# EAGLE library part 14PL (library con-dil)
DIL CABLE CONNECTOR

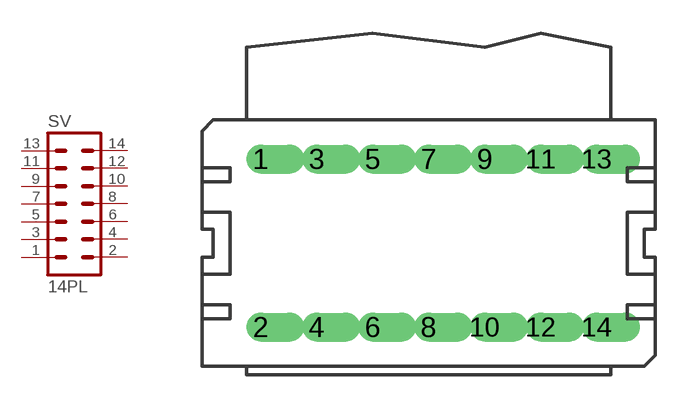
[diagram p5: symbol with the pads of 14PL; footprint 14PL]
Designator prefix SV

## 14PL  [14PL]
1  1  pas
2  2  pas
3  3  pas
4  4  pas
5  5  pas
6  6  pas
7  7  pas
8  8  pas
9  9  pas
10  10  pas
11  11  pas
12  12  pas
13  13  pas
14  14  pas

## Footprint 14PL (pad centres in mm)
DIL CABLE CONNECTOR
drill 0.813 offset: 1 -7.62,3.81; 2 -7.62,-3.81; 3 -5.08,3.81; 4 -5.08,-3.81; 5 -2.54,3.81; 6 -2.54,-3.81; 7 0,3.81; 8 0,-3.81; 9 2.54,3.81; 10 2.54,-3.81; 11 5.08,3.81; 12 5.08,-3.81; 13 7.62,3.81; 14 7.62,-3.81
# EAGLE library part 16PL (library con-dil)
DIL CABLE CONNECTOR

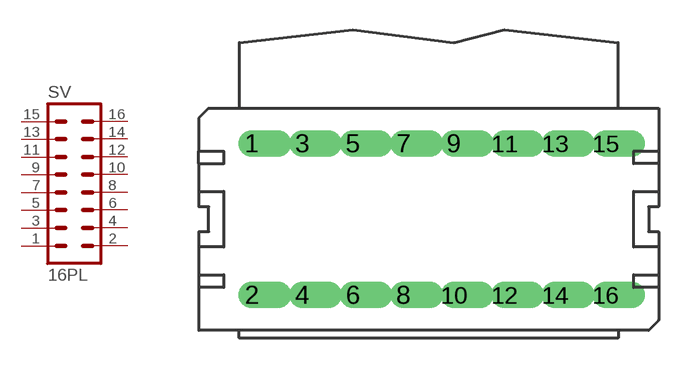
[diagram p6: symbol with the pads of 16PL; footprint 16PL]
Designator prefix SV

## 16PL  [16PL]
1  1  pas
2  2  pas
3  3  pas
4  4  pas
5  5  pas
6  6  pas
7  7  pas
8  8  pas
9  9  pas
10  10  pas
11  11  pas
12  12  pas
13  13  pas
14  14  pas
15  15  pas
16  16  pas

## Footprint 16PL (pad centres in mm)
DIL CABLE CONNECTOR
drill 0.813 offset: 1 -8.89,3.81; 2 -8.89,-3.81; 3 -6.35,3.81; 4 -6.35,-3.81; 5 -3.81,3.81; 6 -3.81,-3.81; 7 -1.27,3.81; 8 -1.27,-3.81; 9 1.27,3.81; 10 1.27,-3.81; 11 3.81,3.81; 12 3.81,-3.81; 13 6.35,3.81; 14 6.35,-3.81; 15 8.89,3.81; 16 8.89,-3.81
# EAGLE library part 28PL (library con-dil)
DIL CABLE CONNECTOR

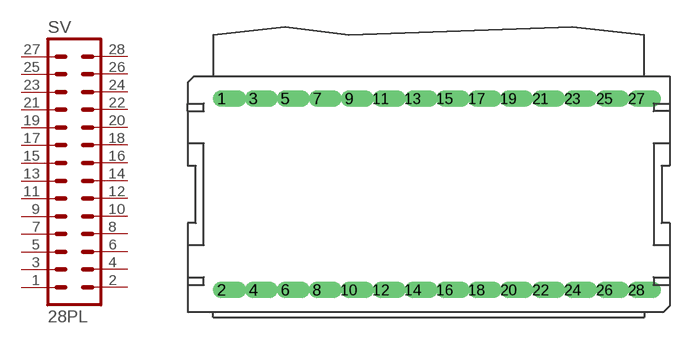
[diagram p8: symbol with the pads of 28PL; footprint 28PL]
Designator prefix SV

## 28PL  [28PL]
1  1  pas
2  2  pas
3  3  pas
4  4  pas
5  5  pas
6  6  pas
7  7  pas
8  8  pas
9  9  pas
10  10  pas
11  11  pas
12  12  pas
13  13  pas
14  14  pas
15  15  pas
16  16  pas
17  17  pas
18  18  pas
19  19  pas
20  20  pas
21  21  pas
22  22  pas
23  23  pas
24  24  pas
25  25  pas
26  26  pas
27  27  pas
28  28  pas

## Footprint 28PL (pad centres in mm)
DIL CABLE CONNECTOR
drill 0.813 offset: 1 -16.51,7.62; 2 -16.51,-7.62; 3 -13.97,7.62; 4 -13.97,-7.62; 5 -11.43,7.62; 6 -11.43,-7.62; 7 -8.89,7.62; 8 -8.89,-7.62; 9 -6.35,7.62; 10 -6.35,-7.62; 11 -3.81,7.62; 12 -3.81,-7.62; 13 -1.27,7.62; 14 -1.27,-7.62; 15 1.27,7.62; 16 1.27,-7.62; 17 3.81,7.62; 18 3.81,-7.62; 19 6.35,7.62; 20 6.35,-7.62; 21 8.89,7.62; 22 8.89,-7.62; 23 11.43,7.62; 24 11.43,-7.62; 25 13.97,7.62; 26 13.97,-7.62; 27 16.51,7.62; 28 16.51,-7.62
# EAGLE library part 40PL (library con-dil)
DIL CABLE CONNECTOR

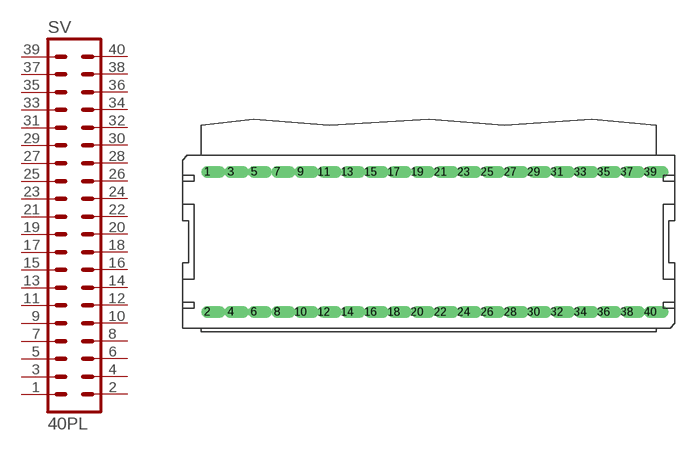
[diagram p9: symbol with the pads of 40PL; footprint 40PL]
Designator prefix SV

## 40PL  [40PL]
1  1  pas
2  2  pas
3  3  pas
4  4  pas
5  5  pas
6  6  pas
7  7  pas
8  8  pas
9  9  pas
10  10  pas
11  11  pas
12  12  pas
13  13  pas
14  14  pas
15  15  pas
16  16  pas
17  17  pas
18  18  pas
19  19  pas
20  20  pas
21  21  pas
22  22  pas
23  23  pas
24  24  pas
25  25  pas
26  26  pas
27  27  pas
28  28  pas
29  29  pas
30  30  pas
31  31  pas
32  32  pas
33  33  pas
34  34  pas
35  35  pas
36  36  pas
37  37  pas
38  38  pas
39  39  pas
40  40  pas

## Footprint 40PL (pad centres in mm)
DIL CABLE CONNECTOR
drill 0.813 offset: 1 -24.13,7.62; 2 -24.13,-7.62; 3 -21.59,7.62; 4 -21.59,-7.62; 5 -19.05,7.62; 6 -19.05,-7.62; 7 -16.51,7.62; 8 -16.51,-7.62; 9 -13.97,7.62; 10 -13.97,-7.62; 11 -11.43,7.62; 12 -11.43,-7.62; 13 -8.89,7.62; 14 -8.89,-7.62; 15 -6.35,7.62; 16 -6.35,-7.62; 17 -3.81,7.62; 18 -3.81,-7.62; 19 -1.27,7.62; 20 -1.27,-7.62; 21 1.27,7.62; 22 1.27,-7.62; 23 3.81,7.62; 24 3.81,-7.62; 25 6.35,7.62; 26 6.35,-7.62; 27 8.89,7.62; 28 8.89,-7.62; 29 11.43,7.62; 30 11.43,-7.62; 31 13.97,7.62; 32 13.97,-7.62; 33 16.51,7.62; 34 16.51,-7.62; 35 19.05,7.62; 36 19.05,-7.62; 37 21.59,7.62; 38 21.59,-7.62; 39 24.13,7.62; 40 24.13,-7.62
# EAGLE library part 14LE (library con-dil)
DIL CABLE CONNECTOR

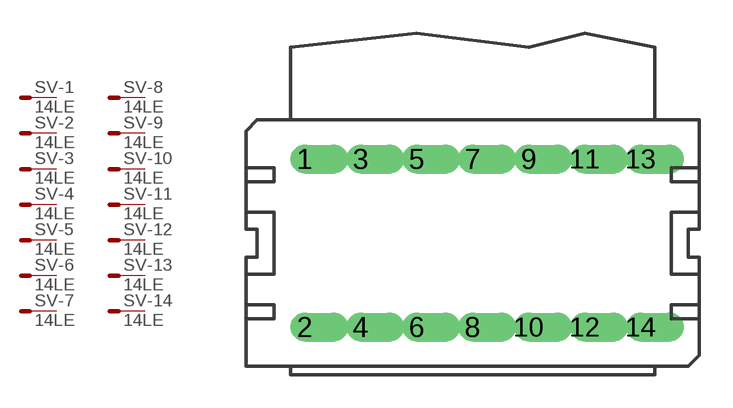
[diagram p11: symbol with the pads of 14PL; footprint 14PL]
Designator prefix SV; gates -1=ST -2=ST -3=ST -4=ST -5=ST -6=ST -7=ST -8=ST -9=ST -10=ST -11=ST -12=ST -13=ST -14=ST

## 14LE  [14PL]
1  -1:S  pas
2  -2:S  pas
3  -3:S  pas
4  -4:S  pas
5  -5:S  pas
6  -6:S  pas
7  -7:S  pas
8  -8:S  pas
9  -9:S  pas
10  -10:S  pas
11  -11:S  pas
12  -12:S  pas
13  -13:S  pas
14  -14:S  pas

## Footprint 14PL (pad centres in mm)
DIL CABLE CONNECTOR
drill 0.813 offset: 1 -7.62,3.81; 2 -7.62,-3.81; 3 -5.08,3.81; 4 -5.08,-3.81; 5 -2.54,3.81; 6 -2.54,-3.81; 7 0,3.81; 8 0,-3.81; 9 2.54,3.81; 10 2.54,-3.81; 11 5.08,3.81; 12 5.08,-3.81; 13 7.62,3.81; 14 7.62,-3.81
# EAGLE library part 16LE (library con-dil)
DIL CABLE CONNECTOR

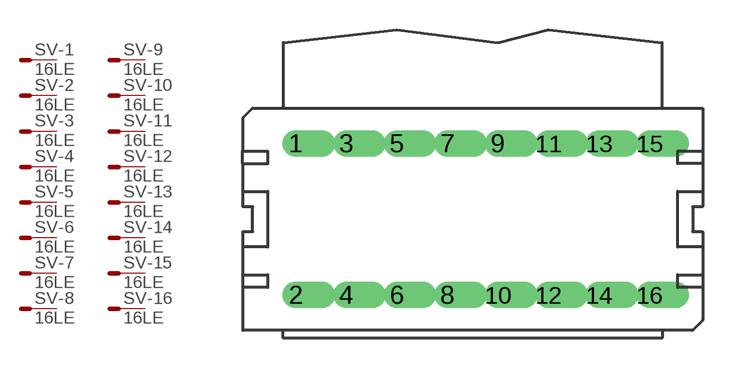
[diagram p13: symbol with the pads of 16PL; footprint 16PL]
Designator prefix SV; gates -1=ST -2=ST -3=ST -4=ST -5=ST -6=ST -7=ST -8=ST -9=ST -10=ST -11=ST -12=ST -13=ST -14=ST -15=ST -16=ST

## 16LE  [16PL]
1  -1:S  pas
2  -2:S  pas
3  -3:S  pas
4  -4:S  pas
5  -5:S  pas
6  -6:S  pas
7  -7:S  pas
8  -8:S  pas
9  -9:S  pas
10  -10:S  pas
11  -11:S  pas
12  -12:S  pas
13  -13:S  pas
14  -14:S  pas
15  -15:S  pas
16  -16:S  pas

## Footprint 16PL (pad centres in mm)
DIL CABLE CONNECTOR
drill 0.813 offset: 1 -8.89,3.81; 2 -8.89,-3.81; 3 -6.35,3.81; 4 -6.35,-3.81; 5 -3.81,3.81; 6 -3.81,-3.81; 7 -1.27,3.81; 8 -1.27,-3.81; 9 1.27,3.81; 10 1.27,-3.81; 11 3.81,3.81; 12 3.81,-3.81; 13 6.35,3.81; 14 6.35,-3.81; 15 8.89,3.81; 16 8.89,-3.81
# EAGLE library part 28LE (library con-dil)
DIL CABLE CONNECTOR

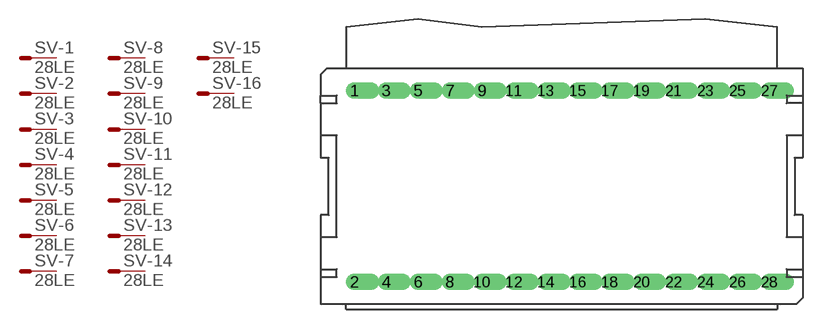
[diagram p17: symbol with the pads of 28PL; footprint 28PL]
Designator prefix SV; gates -1=ST -2=ST -3=ST -4=ST -5=ST -6=ST -7=ST -8=ST -9=ST -10=ST -11=ST -12=ST -13=ST -14=ST -15=ST -16=ST -17=ST -18=ST -19=ST -20=ST -21=ST -22=ST -23=ST -24=ST -25=ST -26=ST -27=ST -28=ST

## 28LE  [28PL]
1  -1:S  pas
2  -2:S  pas
3  -3:S  pas
4  -4:S  pas
5  -5:S  pas
6  -6:S  pas
7  -7:S  pas
8  -8:S  pas
9  -9:S  pas
10  -10:S  pas
11  -11:S  pas
12  -12:S  pas
13  -13:S  pas
14  -14:S  pas
15  -15:S  pas
16  -16:S  pas
17  -17:S  pas
18  -18:S  pas
19  -19:S  pas
20  -20:S  pas
21  -21:S  pas
22  -22:S  pas
23  -23:S  pas
24  -24:S  pas
25  -25:S  pas
26  -26:S  pas
27  -27:S  pas
28  -28:S  pas

## Footprint 28PL (pad centres in mm)
DIL CABLE CONNECTOR
drill 0.813 offset: 1 -16.51,7.62; 2 -16.51,-7.62; 3 -13.97,7.62; 4 -13.97,-7.62; 5 -11.43,7.62; 6 -11.43,-7.62; 7 -8.89,7.62; 8 -8.89,-7.62; 9 -6.35,7.62; 10 -6.35,-7.62; 11 -3.81,7.62; 12 -3.81,-7.62; 13 -1.27,7.62; 14 -1.27,-7.62; 15 1.27,7.62; 16 1.27,-7.62; 17 3.81,7.62; 18 3.81,-7.62; 19 6.35,7.62; 20 6.35,-7.62; 21 8.89,7.62; 22 8.89,-7.62; 23 11.43,7.62; 24 11.43,-7.62; 25 13.97,7.62; 26 13.97,-7.62; 27 16.51,7.62; 28 16.51,-7.62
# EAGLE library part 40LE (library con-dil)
DIL CABLE CONNECTOR

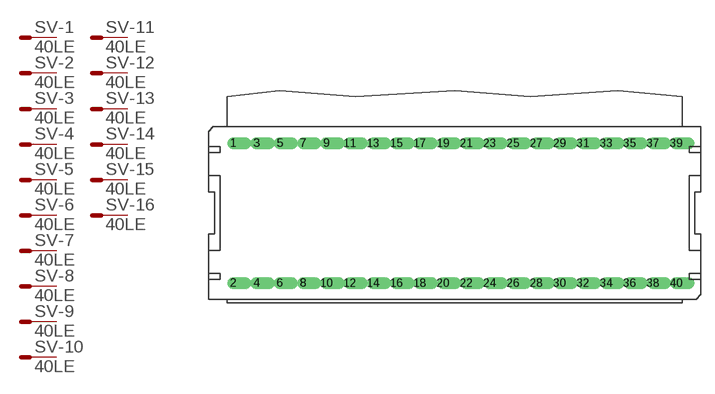
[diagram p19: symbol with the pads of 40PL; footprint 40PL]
Designator prefix SV; gates -1=ST -2=ST -3=ST -4=ST -5=ST -6=ST -7=ST -8=ST -9=ST -10=ST -11=ST -12=ST -13=ST -14=ST -15=ST -16=ST -17=ST -18=ST -19=ST -20=ST -21=ST -22=ST -23=ST -24=ST -25=ST -26=ST -27=ST -28=ST -29=ST -30=ST -31=ST -32=ST -33=ST -34=ST -35=ST -36=ST -37=ST -38=ST -39=ST -40=ST

## 40LE  [40PL]
1  -1:S  pas
2  -2:S  pas
3  -3:S  pas
4  -4:S  pas
5  -5:S  pas
6  -6:S  pas
7  -7:S  pas
8  -8:S  pas
9  -9:S  pas
10  -10:S  pas
11  -11:S  pas
12  -12:S  pas
13  -13:S  pas
14  -14:S  pas
15  -15:S  pas
16  -16:S  pas
17  -17:S  pas
18  -18:S  pas
19  -19:S  pas
20  -20:S  pas
21  -21:S  pas
22  -22:S  pas
23  -23:S  pas
24  -24:S  pas
25  -25:S  pas
26  -26:S  pas
27  -27:S  pas
28  -28:S  pas
29  -29:S  pas
30  -30:S  pas
31  -31:S  pas
32  -32:S  pas
33  -33:S  pas
34  -34:S  pas
35  -35:S  pas
36  -36:S  pas
37  -37:S  pas
38  -38:S  pas
39  -39:S  pas
40  -40:S  pas

## Footprint 40PL (pad centres in mm)
DIL CABLE CONNECTOR
drill 0.813 offset: 1 -24.13,7.62; 2 -24.13,-7.62; 3 -21.59,7.62; 4 -21.59,-7.62; 5 -19.05,7.62; 6 -19.05,-7.62; 7 -16.51,7.62; 8 -16.51,-7.62; 9 -13.97,7.62; 10 -13.97,-7.62; 11 -11.43,7.62; 12 -11.43,-7.62; 13 -8.89,7.62; 14 -8.89,-7.62; 15 -6.35,7.62; 16 -6.35,-7.62; 17 -3.81,7.62; 18 -3.81,-7.62; 19 -1.27,7.62; 20 -1.27,-7.62; 21 1.27,7.62; 22 1.27,-7.62; 23 3.81,7.62; 24 3.81,-7.62; 25 6.35,7.62; 26 6.35,-7.62; 27 8.89,7.62; 28 8.89,-7.62; 29 11.43,7.62; 30 11.43,-7.62; 31 13.97,7.62; 32 13.97,-7.62; 33 16.51,7.62; 34 16.51,-7.62; 35 19.05,7.62; 36 19.05,-7.62; 37 21.59,7.62; 38 21.59,-7.62; 39 24.13,7.62; 40 24.13,-7.62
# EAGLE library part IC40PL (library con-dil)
DIL CABLE CONNECTOR

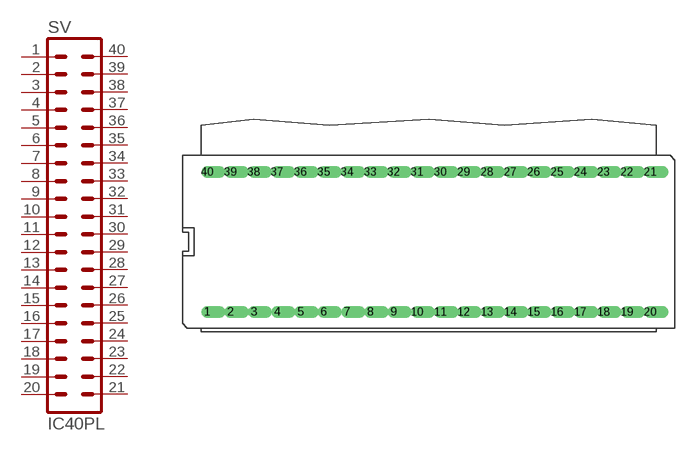
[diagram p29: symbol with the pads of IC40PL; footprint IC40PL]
Designator prefix SV

## IC40PL  [IC40PL]
1  1  pas
2  2  pas
3  3  pas
4  4  pas
5  5  pas
6  6  pas
7  7  pas
8  8  pas
9  9  pas
10  10  pas
11  11  pas
12  12  pas
13  13  pas
14  14  pas
15  15  pas
16  16  pas
17  17  pas
18  18  pas
19  19  pas
20  20  pas
21  21  pas
22  22  pas
23  23  pas
24  24  pas
25  25  pas
26  26  pas
27  27  pas
28  28  pas
29  29  pas
30  30  pas
31  31  pas
32  32  pas
33  33  pas
34  34  pas
35  35  pas
36  36  pas
37  37  pas
38  38  pas
39  39  pas
40  40  pas

## Footprint IC40PL (pad centres in mm)
DIL CABLE CONNECTOR
drill 0.813 offset: 1 -24.13,-7.62; 2 -21.59,-7.62; 3 -19.05,-7.62; 4 -16.51,-7.62; 5 -13.97,-7.62; 6 -11.43,-7.62; 7 -8.89,-7.62; 8 -6.35,-7.62; 9 -3.81,-7.62; 10 -1.27,-7.62; 11 1.27,-7.62; 12 3.81,-7.62; 13 6.35,-7.62; 14 8.89,-7.62; 15 11.43,-7.62; 16 13.97,-7.62; 17 16.51,-7.62; 18 19.05,-7.62; 19 21.59,-7.62; 20 24.13,-7.62; 21 24.13,7.62; 22 21.59,7.62; 23 19.05,7.62; 24 16.51,7.62; 25 13.97,7.62; 26 11.43,7.62; 27 8.89,7.62; 28 6.35,7.62; 29 3.81,7.62; 30 1.27,7.62; 31 -1.27,7.62; 32 -3.81,7.62; 33 -6.35,7.62; 34 -8.89,7.62; 35 -11.43,7.62; 36 -13.97,7.62; 37 -16.51,7.62; 38 -19.05,7.62; 39 -21.59,7.62; 40 -24.13,7.62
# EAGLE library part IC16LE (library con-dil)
DIL CABLE CONNECTOR

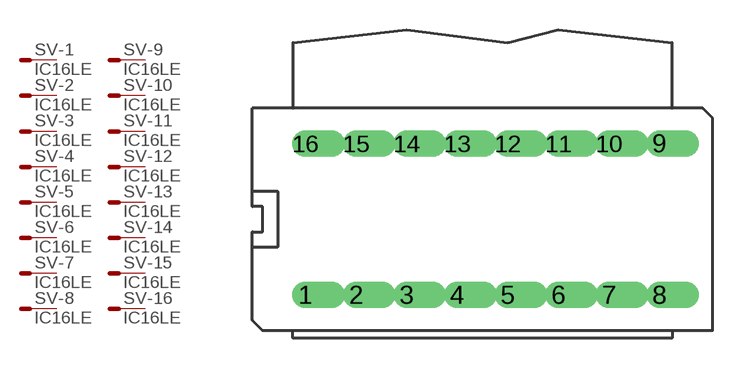
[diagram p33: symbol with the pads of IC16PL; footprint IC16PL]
Designator prefix SV; gates -1=ICST -2=ICST -3=ICST -4=ICST -5=ICST -6=ICST -7=ICST -8=ICST -9=ICST -10=ICST -11=ICST -12=ICST -13=ICST -14=ICST -15=ICST -16=ICST

## IC16LE  [IC16PL]
1  -1:S  pas
2  -2:S  pas
3  -3:S  pas
4  -4:S  pas
5  -5:S  pas
6  -6:S  pas
7  -7:S  pas
8  -8:S  pas
9  -9:S  pas
10  -10:S  pas
11  -11:S  pas
12  -12:S  pas
13  -13:S  pas
14  -14:S  pas
15  -15:S  pas
16  -16:S  pas

## Footprint IC16PL (pad centres in mm)
DIL CABLE CONNECTOR
drill 0.813 offset: 1 -8.89,-3.81; 2 -6.35,-3.81; 3 -3.81,-3.81; 4 -1.27,-3.81; 5 1.27,-3.81; 6 3.81,-3.81; 7 6.35,-3.81; 8 8.89,-3.81; 9 8.89,3.81; 10 6.35,3.81; 11 3.81,3.81; 12 1.27,3.81; 13 -1.27,3.81; 14 -3.81,3.81; 15 -6.35,3.81; 16 -8.89,3.81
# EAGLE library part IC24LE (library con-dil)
DIL CABLE CONNECTOR

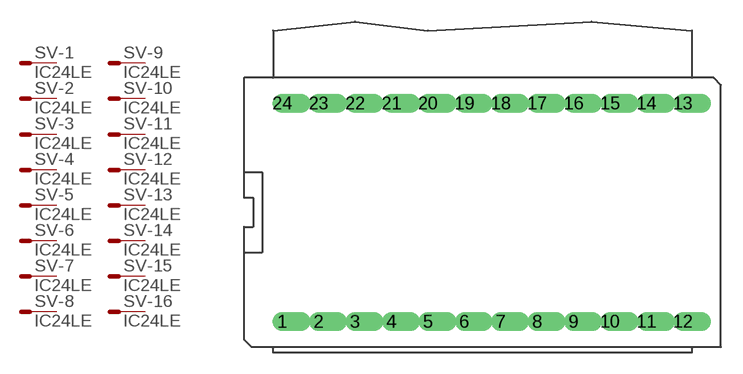
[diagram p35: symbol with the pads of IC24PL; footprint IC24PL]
Designator prefix SV; gates -1=ICST -2=ICST -3=ICST -4=ICST -5=ICST -6=ICST -7=ICST -8=ICST -9=ICST -10=ICST -11=ICST -12=ICST -13=ICST -14=ICST -15=ICST -16=ICST -17=ICST -18=ICST -19=ICST -20=ICST -21=ICST -22=ICST -23=ICST -24=ICST

## IC24LE  [IC24PL]
1  -1:S  pas
2  -2:S  pas
3  -3:S  pas
4  -4:S  pas
5  -5:S  pas
6  -6:S  pas
7  -7:S  pas
8  -8:S  pas
9  -9:S  pas
10  -10:S  pas
11  -11:S  pas
12  -12:S  pas
13  -13:S  pas
14  -14:S  pas
15  -15:S  pas
16  -16:S  pas
17  -17:S  pas
18  -18:S  pas
19  -19:S  pas
20  -20:S  pas
21  -21:S  pas
22  -22:S  pas
23  -23:S  pas
24  -24:S  pas

## Footprint IC24PL (pad centres in mm)
DIL CABLE CONNECTOR
drill 0.813 offset: 1 -13.97,-7.62; 2 -11.43,-7.62; 3 -8.89,-7.62; 4 -6.35,-7.62; 5 -3.81,-7.62; 6 -1.27,-7.62; 7 1.27,-7.62; 8 3.81,-7.62; 9 6.35,-7.62; 10 8.89,-7.62; 11 11.43,-7.62; 12 13.97,-7.62; 13 13.97,7.62; 14 11.43,7.62; 15 8.89,7.62; 16 6.35,7.62; 17 3.81,7.62; 18 1.27,7.62; 19 -1.27,7.62; 20 -3.81,7.62; 21 -6.35,7.62; 22 -8.89,7.62; 23 -11.43,7.62; 24 -13.97,7.62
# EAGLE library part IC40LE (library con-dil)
DIL CABLE CONNECTOR

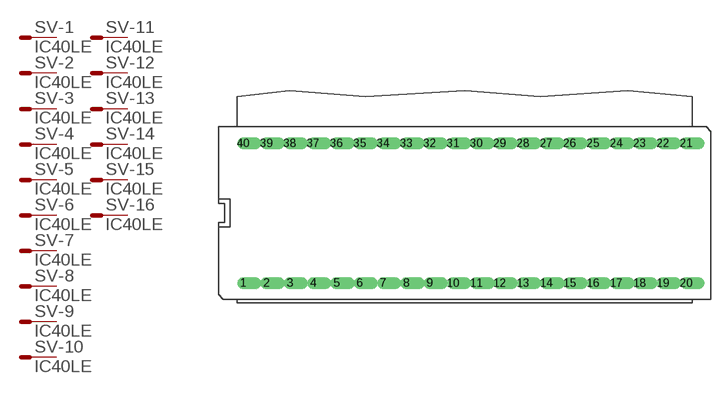
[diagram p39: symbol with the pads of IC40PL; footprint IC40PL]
Designator prefix SV; gates -1=ICST -2=ICST -3=ICST -4=ICST -5=ICST -6=ICST -7=ICST -8=ICST -9=ICST -10=ICST -11=ICST -12=ICST -13=ICST -14=ICST -15=ICST -16=ICST -17=ICST -18=ICST -19=ICST -20=ICST -21=ICST -22=ICST -23=ICST -24=ICST -25=ICST -26=ICST -27=ICST -28=ICST -29=ICST -30=ICST -31=ICST -32=ICST -33=ICST -34=ICST -35=ICST -36=ICST -37=ICST -38=ICST -39=ICST -40=ICST

## IC40LE  [IC40PL]
1  -1:S  pas
2  -2:S  pas
3  -3:S  pas
4  -4:S  pas
5  -5:S  pas
6  -6:S  pas
7  -7:S  pas
8  -8:S  pas
9  -9:S  pas
10  -10:S  pas
11  -11:S  pas
12  -12:S  pas
13  -13:S  pas
14  -14:S  pas
15  -15:S  pas
16  -16:S  pas
17  -17:S  pas
18  -18:S  pas
19  -19:S  pas
20  -20:S  pas
21  -21:S  pas
22  -22:S  pas
23  -23:S  pas
24  -24:S  pas
25  -25:S  pas
26  -26:S  pas
27  -27:S  pas
28  -28:S  pas
29  -29:S  pas
30  -30:S  pas
31  -31:S  pas
32  -32:S  pas
33  -33:S  pas
34  -34:S  pas
35  -35:S  pas
36  -36:S  pas
37  -37:S  pas
38  -38:S  pas
39  -39:S  pas
40  -40:S  pas

## Footprint IC40PL (pad centres in mm)
DIL CABLE CONNECTOR
drill 0.813 offset: 1 -24.13,-7.62; 2 -21.59,-7.62; 3 -19.05,-7.62; 4 -16.51,-7.62; 5 -13.97,-7.62; 6 -11.43,-7.62; 7 -8.89,-7.62; 8 -6.35,-7.62; 9 -3.81,-7.62; 10 -1.27,-7.62; 11 1.27,-7.62; 12 3.81,-7.62; 13 6.35,-7.62; 14 8.89,-7.62; 15 11.43,-7.62; 16 13.97,-7.62; 17 16.51,-7.62; 18 19.05,-7.62; 19 21.59,-7.62; 20 24.13,-7.62; 21 24.13,7.62; 22 21.59,7.62; 23 19.05,7.62; 24 16.51,7.62; 25 13.97,7.62; 26 11.43,7.62; 27 8.89,7.62; 28 6.35,7.62; 29 3.81,7.62; 30 1.27,7.62; 31 -1.27,7.62; 32 -3.81,7.62; 33 -6.35,7.62; 34 -8.89,7.62; 35 -11.43,7.62; 36 -13.97,7.62; 37 -16.51,7.62; 38 -19.05,7.62; 39 -21.59,7.62; 40 -24.13,7.62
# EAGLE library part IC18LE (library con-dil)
DIL CABLE CONNECTOR

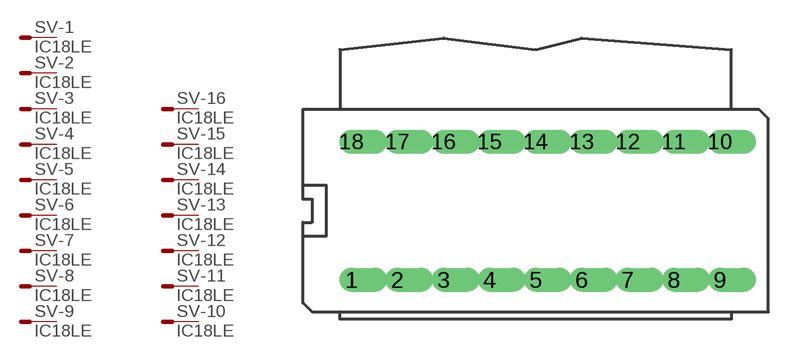
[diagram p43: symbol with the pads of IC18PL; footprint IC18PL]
Designator prefix SV; gates -1=ICST -2=ICST -3=ICST -4=ICST -5=ICST -6=ICST -7=ICST -8=ICST -9=ICST -10=ICST -11=ICST -12=ICST -13=ICST -14=ICST -15=ICST -16=ICST -17=ICST -18=ICST

## IC18LE  [IC18PL]
1  -1:S  pas
2  -2:S  pas
3  -3:S  pas
4  -4:S  pas
5  -5:S  pas
6  -6:S  pas
7  -7:S  pas
8  -8:S  pas
9  -9:S  pas
10  -10:S  pas
11  -11:S  pas
12  -12:S  pas
13  -13:S  pas
14  -14:S  pas
15  -15:S  pas
16  -16:S  pas
17  -17:S  pas
18  -18:S  pas

## Footprint IC18PL (pad centres in mm)
DIL CABLE CONNECTOR
drill 0.813 offset: 1 -10.16,-3.81; 2 -7.62,-3.81; 3 -5.08,-3.81; 4 -2.54,-3.81; 5 0,-3.81; 6 2.54,-3.81; 7 5.08,-3.81; 8 7.62,-3.81; 9 10.16,-3.81; 10 10.16,3.81; 11 7.62,3.81; 12 5.08,3.81; 13 2.54,3.81; 14 0,3.81; 15 -2.54,3.81; 16 -5.08,3.81; 17 -7.62,3.81; 18 -10.16,3.81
